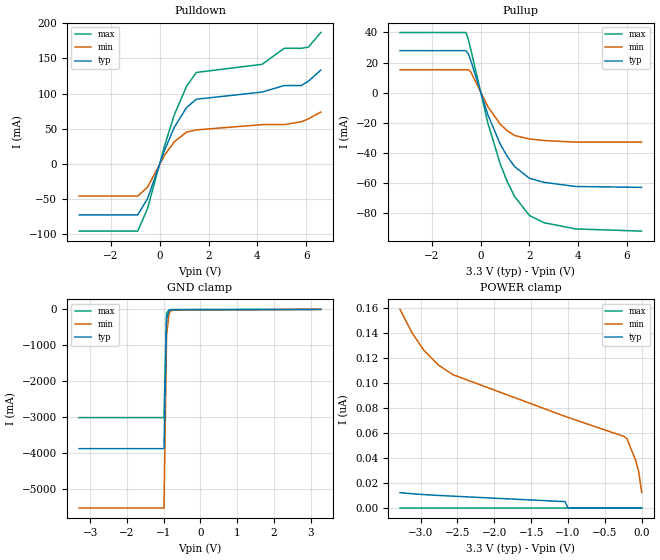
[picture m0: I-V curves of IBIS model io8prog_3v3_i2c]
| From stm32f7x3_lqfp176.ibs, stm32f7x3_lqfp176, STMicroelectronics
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[Model]  io8prog_3v3_i2c
Model_type I/O
Polarity   Non-Inverting
Enable   Active-Low
Vinl =   0.540000V
Vinh =   1.260000V
Vmeas =  0.900000V
Cref =   100.000000nF
Rref =   1.000000k
Vref =   1.800000V
C_comp   2.577900pF   2.407400pF   2.792100pF
[Temperature Range]   25.000000   0.125000k   -40.000000
[Pullup Reference]   3.300000V   2.700000V   3.600000V
[Pulldown Reference]   0.0V   0.0V   0.0V
[POWER Clamp Reference]   3.300000V   2.700000V   3.600000V
[GND Clamp Reference]   0.0V   0.0V   0.0V
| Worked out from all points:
|   slope of the pulldown table from 0 to 0.495 V, typ, clamps not added: 11.1 ohm
|   slope of the pullup table from 0 to 0.495 V, typ, clamps not added: 21.7 ohm
|   GND clamp passes 1 mA (typ) near -0.57 V on its own axis
[Pulldown]
|Voltage   I(typ)   I(min)   I(max)
-3.3V     -72.19mA   -45.43mA   -95.27mA
-900mV    -72.19mA   -45.43mA   -95.27mA
-500mV    -49.3mA    -32.97mA   -63.37mA
200mV     19.68mA    12.49mA    25.95mA
600mV     52.23mA    31.69mA    69.99mA
1.1V      80.2mA     45.29mA    110.3mA
1.5V      91.99mA    48.41mA    130mA
4.2V      102.2mA    55.95mA    141.6mA
5.1V      111.4mA    55.95mA    164.3mA
5.8V      111.4mA    59.96mA    164.3mA
6.1V      117.8mA    64.19mA    166.1mA
6.6V      133.3mA    73.83mA    186.7mA
[Pullup]
|Voltage   I(typ)   I(min)   I(max)
-3.3V     27.94mA    15.3mA     39.98mA
-600mV    27.94mA    15.3mA     39.98mA
-500mV    25.89mA    15.3mA     35.29mA
-400mV    21.3mA     13.82mA    28.75mA
300mV     -14.62mA   -9.248mA   -20.15mA
800mV     -33.8mA    -20.67mA   -46.89mA
1.1V      -42.41mA   -25.28mA   -59.19mA
1.4V      -49.01mA   -28.29mA   -68.91mA
2V        -56.64mA   -30.64mA   -81.32mA
2.6V      -59.37mA   -31.63mA   -86.14mA
3.9V      -62.11mA   -32.7mA    -90.25mA
6.6V      -62.7mA    -32.7mA    -91.7mA
[GND_clamp]
|Voltage   I(typ)   I(min)   I(max)
-3.3V     -3.872A    -5.523A    -3.009A
-990mV    -3.872A    -5.523A    -3.009A
-920mV    -262.2mA   -719.6mA   -104.3mA
-850mV    -25.19mA   -100.9mA   -13.07mA
-780mV    -6.959mA   -18mA      -7.19mA
3.28V     0A         5.665nA    0A
[POWER_clamp]
|Voltage   I(typ)   I(min)   I(max)
-3.28V    12.28nA    159nA      0A
-3.12V    11.42nA    140.5nA    0A
-2.96V    10.74nA    126.5nA    0A
-2.76V    10.06nA    114.5nA    0A
-2.56V    9.465nA    106.7nA    0A
-1.04V    5.098nA    73.34nA    0A
-1V       0A         72.52nA    0A
-240mV    0A         57.28nA    0A
-200mV    0A         55.46nA    0A
-80mV     0A         38nA       0A
-40mV     0A         29.01nA    0A
0V        0A         12.48nA    0A
[Ramp]
| variable   typ   min   max
dV/dt_r  1.29876/6.00000u   0.82878/6.00000u   1.59366/6.00000u
dV/dt_f  1.60810/6.00000u   1.14585/6.00000u   1.85006/6.00000u
R_load = 50.000000
